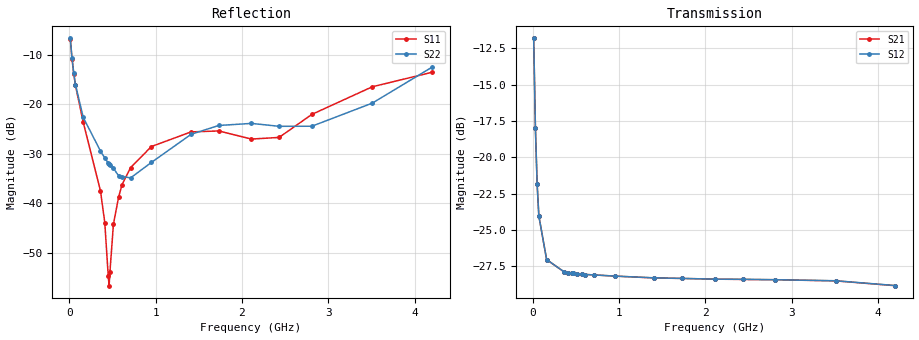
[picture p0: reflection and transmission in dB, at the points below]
! Integrated Device Technology
! Corporate Headquarters
! 6024 Silver Creek Valley Road
! San Jose, CA 95138  USA
! Phone:  1-408-284-8200
! Toll Free:  1-800-223-1366
! Webpage:  http://www.idt.com/
! Timing and RF Division
! 515 Groton Road, Suite 102
! Westford, MA 01886-6024
! Device:  F1950
! Description: 7-bit 0.25 dB Digital Step Attenuator
! Frequency:  150.0 -  4000.00 MHz
! Package:  4x4 mm Thin QFN Plastic Package: 24 pin
! Ports:  2 RF, 12 DC
!  Pin  1  = D0
!  Pin  2  = VDD
!  Pin  3  = Vmode
!  Pin  4  = GND
!  Pin  5  = RF1  =  Port 1
!  Pin  6  = GND
!  Pin  7  = GND
!  Pin  8  = GND
!  Pin  9  = GND
!  Pin 10  = GND
!  Pin 11  = GND
!  Pin 12  = GND
!  Pin 13  = GND
!  Pin 14  = RF2  =  Port 2
!  Pin 15  = GND
!  Pin 16  = LE
!  Pin 17  = CLK
!  Pin 18  = DATE
!  Pin 19  = D6
!  Pin 20  = D5
!  Pin 21  = D4
!  Pin 22  = D3
!  Pin 23  = D2
!  Pin 24  = D1
! State:  109
! Atten State:  27.25 dB
! Voltage:  +5.00 Volts
! Current:  Not Measured mA
! Data:  The device was measured on a the F195X evaluation board which has
!  individual transmission lines to the RF pins.  Data was collected
!  using a calibrated network analyzer.  The evaluation board was
!  de-embedded using a TRL calibration technique.
!  The reference plane is the edge of the package pin.
! Misc:  Board 2019
!  Action Tracker AT0250
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# GHz S dB R 50
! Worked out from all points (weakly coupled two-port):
!   420 points, 10 MHz to 4.2 GHz, reference 50 ohm
!   highest |S21| = -11.82 dB at 10 MHz (marker M1); lowest = -28.8 dB at 4.2 GHz (marker M2)
!   lowest |S11| = -56.7 dB at 460 MHz (marker M3), VSWR 1.00, Z = 49.9 - j0.0514 ohm
!   |S11| at or under -10 dB: 26.28 MHz to end of sweep
!   |S22| runs from -35.2 to -6.6 dB; largest |S21 - S12| = 9.2e-05
!   S11 on the Smith chart (normalised r, x): 10 MHz: 1.99, -1.09; 30 MHz: 1.29, -0.63; 70 MHz: 1.09, -0.32; 450 MHz: 1.00, -0.00; 4.2 GHz: 0.69, +0.17
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0.01  -6.71 -27.6  -11.82 -37.8  -11.82 -37.8  -6.61 -28.5
0.03  -10.69 -49.9  -18.01 -55.6  -18.01 -55.6  -10.60 -51.5
0.05  -13.76 -60.0  -21.86 -53.5  -21.86 -53.5  -13.58 -61.7
0.07  -16.14 -65.6  -24.05 -47.2  -24.05 -47.2  -15.97 -66.9
0.16  -23.59 -72.0  -27.05 -27.6  -27.04 -27.6  -22.61 -75.5
0.36  -37.52 -69.1  -27.88 -16.3  -27.88 -16.3  -29.44 -85.6
0.41  -43.95 -76.5  -27.94 -15.3  -27.94 -15.4  -30.85 -87.8
0.45  -54.76 -116.2  -27.97 -14.8  -27.97 -14.8  -31.89 -93.5
0.46  -56.72 -159.3  -27.98 -14.7  -27.98 -14.7  -32.08 -95.2
0.47  -53.85 163.4  -27.99 -14.6  -27.99 -14.7  -32.23 -96.9
0.51  -44.27 139.3  -28.01 -14.3  -28.01 -14.3  -32.92 -100.9
0.57  -38.79 134.1  -28.05 -14.1  -28.04 -14.1  -34.45 -111.6
0.61  -36.22 135.9  -28.07 -14.0  -28.07 -14.0  -34.61 -120.0
0.71  -32.78 137.5  -28.10 -14.1  -28.10 -14.1  -34.87 -139.8
0.95  -28.53 145.9  -28.18 -15.0  -28.18 -15.0  -31.75 -176.9
1.41  -25.56 162.5  -28.31 -17.8  -28.30 -17.8  -26.05 160.2
1.73  -25.37 167.6  -28.34 -20.1  -28.34 -20.1  -24.26 151.8
2.11  -27.01 157.0  -28.39 -23.6  -28.39 -23.6  -23.84 141.9
2.43  -26.68 125.5  -28.41 -26.0  -28.40 -26.0  -24.43 131.1
2.81  -22.01 104.9  -28.43 -29.6  -28.43 -29.7  -24.41 115.6
3.51  -16.42 117.1  -28.51 -35.8  -28.50 -35.9  -19.73 113.0
4.2  -13.49 145.3  -28.84 -39.7  -28.83 -39.8  -12.47 127.0
